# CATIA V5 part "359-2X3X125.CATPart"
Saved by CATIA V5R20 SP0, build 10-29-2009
Part number: 359-2X3X125
Definition: NONE
Nomenclature: 359-2X3X125
Source: Unknown
Description: 359-2X3X125
Bounding box of the stored display mesh (mm): x -3 to 122, y -3 to 3, z -3 to 3
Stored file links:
  C:\Users\Utente\Desktop\IO LAVORO\3D X SITO CF\X SITO\PLASTICA\359\359-2X3X125.CATPart

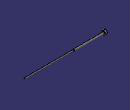
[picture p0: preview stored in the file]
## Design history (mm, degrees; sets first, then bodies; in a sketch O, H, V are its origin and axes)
Body1 "359-2X3X125" (main body)
  Solid1: solid without history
